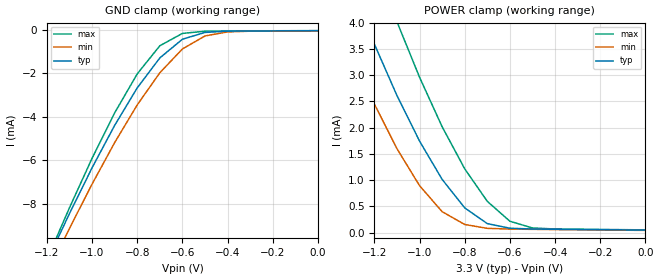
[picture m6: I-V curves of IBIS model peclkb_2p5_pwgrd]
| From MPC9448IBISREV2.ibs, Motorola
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|This model is for a 2.5V Pecl_bar Input with a 25,000 ohm pull_up
[Model]   peclkb_2p5_pwgrd
Model_type   Input
Vmeas=1.25
Vinl=0.7
Vinh=1.7
| Variable   typ   min   max
C_comp   5p   5p   5p
[Temperature Range]   27.00   100.00   -45.00
[Power Clamp Reference]   3.30V   3.00V   3.60V
[Gnd Clamp Reference]   0.000V   0.000V   0.000V
[Voltage Range]   3.30V   3.00V   3.60V
[Pulldown Reference]   0.000V   0.000V   0.000V
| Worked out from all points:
|   GND clamp passes 1 mA (typ) near -0.67 V on its own axis
|   POWER clamp passes 1 mA (typ) near -0.90 V on its own axis
[GND_clamp]
| voltage   I(typ)   I(min)   I(max)
-2.5V     -42.46mA   -42.1mA    -44.26mA
-1.2V     -10.66mA   -11.27mA   -10.58mA
-1.1V     -8.454mA   -9.137mA   -8.187mA
-1V       -6.351mA   -7.101mA   -5.915mA
-900mV    -4.402mA   -5.192mA   -3.826mA
-800mV    -2.678mA   -3.459mA   -2.033mA
-700mV    -1.299mA   -1.982mA   -740.6uA
-600mV    -440.2uA   -888.6uA   -173.5uA
-500mV    -127.7uA   -289.8uA   -72.46uA
-400mV    -70.72uA   -104.1uA   -60.68uA
1.08fV    -49.5uA    -54.46uA   -44.55uA
[POWER_clamp]
| voltage   I(typ)  I(min)  I(max)
-2.5V     21.07mA    19.22mA    23.58mA
-1.4V     5.809mA    4.452mA    7.665mA
-1.3V     4.66mA     3.406mA    6.383mA
-1.2V     3.589mA    2.448mA    5.161mA
-1.1V     2.61mA     1.599mA    4.014mA
-1V       1.743mA    895.3uA    2.959mA
-900mV    1.015mA    400.4uA    2.017mA
-800mV    472.1uA    156.7uA    1.216mA
-700mV    173.4uA    83.32uA    596.6uA
-600mV    85.44uA    69.53uA    218.1uA
-500mV    70.34uA    64.47uA    90.36uA
1.08fV    49.5uA     44.56uA    54.45uA
